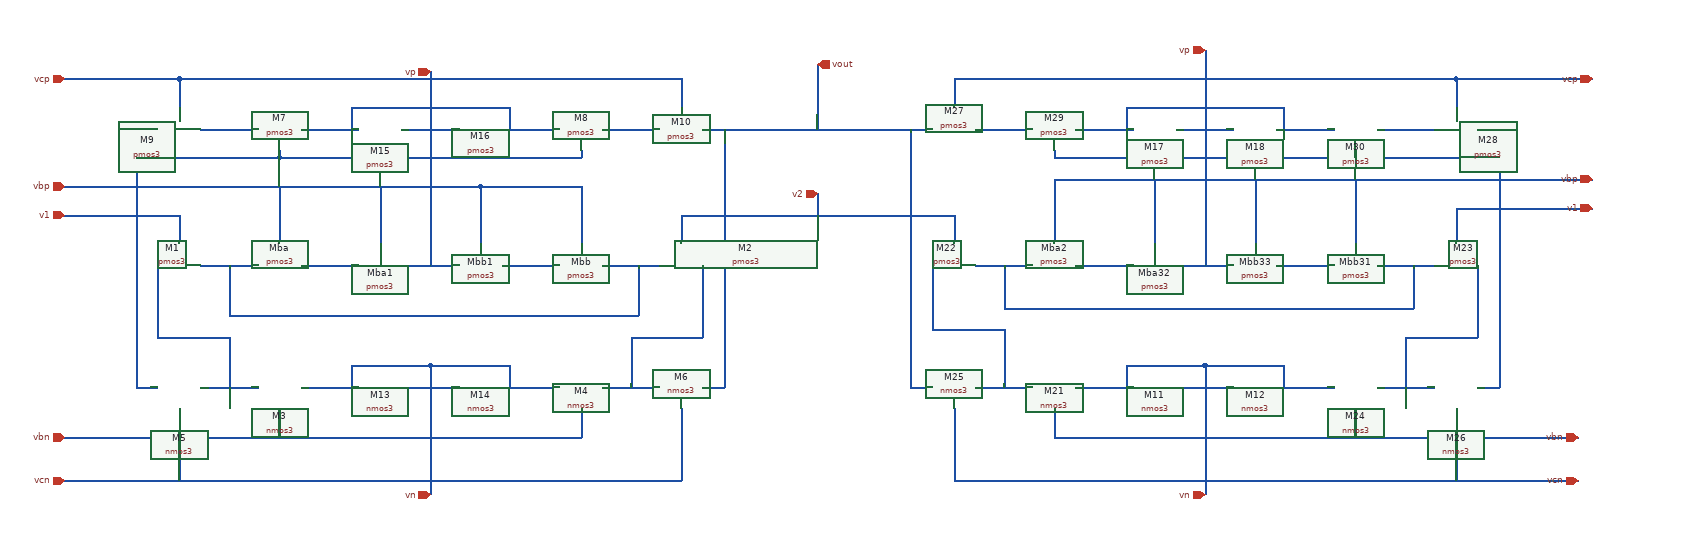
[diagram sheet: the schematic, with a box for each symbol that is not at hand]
v {xschem version=2.9.9 file_version=1.2 }
G {}
K {}
V {}
S {}
E {}
N -580 -180 -500 -180 { lab=vp}
N -540 -260 -540 -180 { lab=vp}
N -750 -150 -750 -140 { lab=#net1}
N -610 -140 -470 -140 { lab=#net1}
N -330 -150 -330 -140 { lab=#net1}
N -860 -180 -780 -180 { lab=#net2}
N -300 -180 -220 -180 { lab=#net3}
N -890 -250 -890 -210 { lab=vcp}
N -750 -250 -330 -250 { lab=vcp}
N -190 -250 -190 -210 { lab=vcp}
N -930 -250 -890 -250 { lab=vcp}
N -920 -140 -750 -140 { lab=#net1}
N -160 -180 -60 -180 { lab=vout}
N -950 -180 -920 -180 { lab=#net1}
N -950 -180 -950 180 { lab=#net1}
N -950 180 -920 180 { lab=#net1}
N -950 -140 -920 -140 { lab=#net1}
N -860 10 -780 10 { lab=#net4}
N -300 10 -220 10 { lab=#net5}
N -860 180 -780 180 { lab=#net6}
N -540 180 -540 200 { lab=vn}
N -300 180 -220 180 { lab=#net7}
N -160 180 -130 180 { lab=vout}
N -130 -180 -130 180 { lab=vout}
N -190 210 -190 310 { lab=vcn}
N -890 210 -890 310 { lab=vcn}
N -860 310 -330 310 { lab=vcn}
N -850 250 -470 250 { lab=vbn}
N -750 210 -750 250 { lab=vbn}
N -330 210 -330 250 { lab=vbn}
N -580 10 -500 10 { lab=vp}
N -540 -180 -540 10 { lab=vp}
N -190 -60 -190 -20 { lab=v2}
N -890 -60 -890 -20 { lab=v1}
N -1050 -60 -890 -60 { lab=v1}
N -750 -100 -750 -20 { lab=vbp}
N -910 -100 -470 -100 { lab=vbp}
N -330 -100 -330 -20 { lab=vbp}
N -920 10 -920 110 { lab=#net6}
N -920 110 -820 110 { lab=#net6}
N -160 10 -160 110 { lab=#net7}
N -260 110 -160 110 { lab=#net7}
N -260 110 -260 180 { lab=#net7}
N -820 110 -820 180 { lab=#net6}
N -720 10 -640 10 { lab=#net8}
N -610 -100 -610 -20 { lab=vbp}
N -1050 -100 -910 -100 { lab=vbp}
N -1000 250 -850 250 { lab=vbn}
N -1000 310 -860 310 { lab=vcn}
N -440 10 -360 10 { lab=#net9}
N -890 -250 -750 -250 { lab=vcp}
N -330 -250 -190 -250 { lab=vcp}
N -470 -140 -330 -140 { lab=#net1}
N -750 -140 -610 -140 { lab=#net1}
N -470 -100 -330 -100 { lab=vbp}
N -470 250 -330 250 { lab=vbn}
N -330 310 -190 310 { lab=vcn}
N -470 -100 -470 -20 { lab=vbp}
N -60 -180 160 -180 { lab=vout}
N 0 -270 0 -180 { lab=vout}
N 130 -180 130 180 { lab=vout}
N 130 180 160 180 { lab=vout}
N -50 -60 190 -60 { lab=v2}
N -190 -60 -50 -60 { lab=v2}
N 0 -90 0 -60 { lab=v2}
N 190 210 190 310 { lab=vcn}
N 890 210 890 310 { lab=vcn}
N 330 210 330 250 { lab=vbn}
N 750 210 750 250 { lab=vbn}
N 920 -180 950 -180 { lab=#net10}
N 950 -180 950 180 { lab=#net10}
N 920 180 950 180 { lab=#net10}
N 780 -180 860 -180 { lab=#net11}
N 780 180 860 180 { lab=#net12}
N 820 110 820 180 { lab=#net12}
N 820 110 920 110 { lab=#net12}
N 920 10 920 110 { lab=#net12}
N 780 10 860 10 { lab=#net13}
N 640 10 720 10 { lab=#net14}
N 500 10 580 10 { lab=vp}
N 360 10 440 10 { lab=#net15}
N 220 10 300 10 { lab=#net16}
N 330 -150 330 -140 { lab=#net10}
N 330 -140 950 -140 { lab=#net10}
N 750 -150 750 -140 { lab=#net10}
N 190 -250 890 -250 { lab=vcp}
N 190 -250 190 -210 { lab=vcp}
N 890 -250 890 -210 { lab=vcp}
N 330 -110 1080 -110 { lab=vbp}
N 470 -110 470 -20 { lab=vbp}
N 610 -110 610 -20 { lab=vbp}
N 330 250 1060 250 { lab=vbn}
N 190 310 1060 310 { lab=vcn}
N 540 -290 540 10 { lab=vp}
N 470 150 540 150 { lab=vn}
N 540 150 540 180 { lab=vn}
N 540 150 610 150 { lab=vn}
N 540 180 540 330 { lab=vn}
N -610 150 -540 150 { lab=vn}
N -540 150 -540 180 { lab=vn}
N -540 150 -470 150 { lab=vn}
N -540 200 -540 330 { lab=vn}
N -610 -210 -540 -210 { lab=vp}
N -540 -210 -470 -210 { lab=vp}
N 470 -210 540 -210 { lab=vp}
N 540 -210 610 -210 { lab=vp}
N 640 -180 720 -180 { lab=vp}
N 360 -180 440 -180 { lab=vp}
N 430 -210 430 -180 { lab=vp}
N 430 -210 470 -210 { lab=vp}
N 610 -210 650 -210 { lab=vp}
N 650 -210 650 -180 { lab=vp}
N -650 -210 -610 -210 { lab=vp}
N -650 -210 -650 -180 { lab=vp}
N -470 -210 -430 -210 { lab=vp}
N -430 -210 -430 -180 { lab=vp}
N -720 -180 -640 -180 { lab=vp}
N -440 -180 -360 -180 { lab=vp}
N -720 180 -640 180 { lab=vn}
N -650 150 -650 180 { lab=vn}
N -650 150 -610 150 { lab=vn}
N -470 150 -430 150 { lab=vn}
N -430 150 -430 180 { lab=vn}
N -440 180 -360 180 { lab=vn}
N -580 180 -500 180 { lab=vn}
N 360 180 440 180 { lab=vn}
N 430 150 430 180 { lab=vn}
N 430 150 470 150 { lab=vn}
N 610 150 650 150 { lab=vn}
N 650 150 650 180 { lab=vn}
N 500 180 580 180 { lab=vn}
N 640 180 720 180 { lab=vn}
N 220 -180 300 -180 { lab=#net17}
N 890 -70 890 -20 { lab=v1}
N 890 -70 1080 -70 { lab=v1}
N -1050 -250 -930 -250 { lab=vcp}
N -1050 250 -1000 250 { lab=vbn}
N -1050 310 -1000 310 { lab=vcn}
N 330 -110 330 -20 { lab=vbp}
N 750 -110 750 -20 { lab=vbp}
N 190 -60 190 -20 { lab=v2}
N 890 -250 1080 -250 { lab=vcp}
N 160 10 160 100 { lab=#net18}
N 160 100 260 100 { lab=#net18}
N 260 100 260 180 { lab=#net18}
N 220 180 300 180 { lab=#net18}
N 500 -180 540 -180 { lab=vp}
N 540 -180 580 -180 { lab=vp}
N -820 10 -820 80 {}
N -820 80 -250 80 {}
N -250 10 -250 80 {}
N 260 10 260 70 {}
N 260 70 830 70 {}
N 830 10 830 70 {}
C {madvlsi/pmos3.sym} -750 10 1 0 {name=Mba
L=0.5
W=6
body=VDD
nf=1
mult=1
ad="'int((nf+1)/2) * W/nf * 0.29'" 
pd="'2*int((nf+1)/2) * (W/nf + 0.29)'"
as="'int((nf+2)/2) * W/nf * 0.29'" 
ps="'2*int((nf+2)/2) * (W/nf + 0.29)'"
nrd="'0.29 / W'" nrs="'0.29 / W'"
sa=0 sb=0 sd=0
model=pfet_01v8
spiceprefix=X
}
C {madvlsi/nmos3.sym} -750 180 3 0 {name=M3
L=0.5
W=6
body=GND
nf=1
mult=1
ad="'int((nf+1)/2) * W/nf * 0.29'" 
pd="'2*int((nf+1)/2) * (W/nf + 0.29)'"
as="'int((nf+2)/2) * W/nf * 0.29'" 
ps="'2*int((nf+2)/2) * (W/nf + 0.29)'"
nrd="'0.29 / W'" nrs="'0.29 / W'"
sa=0 sb=0 sd=0
model=nfet_01v8
spiceprefix=X
}
C {madvlsi/pmos3.sym} -890 10 1 0 {name=M1
L=0.5
W=6
body=VDD
nf=1
mult=1
ad="'int((nf+1)/2) * W/nf * 0.29'" 
pd="'2*int((nf+1)/2) * (W/nf + 0.29)'"
as="'int((nf+2)/2) * W/nf * 0.29'" 
ps="'2*int((nf+2)/2) * (W/nf + 0.29)'"
nrd="'0.29 / W'" nrs="'0.29 / W'"
sa=0 sb=0 sd=0
model=pfet_01v8
spiceprefix=X
}
C {madvlsi/pmos3.sym} -190 10 1 0 {name=M2
L=0.5
W=6
body=VDD
nf=1
mult=1
ad="'int((nf+1)/2) * W/nf * 0.29'" 
pd="'2*int((nf+1)/2) * (W/nf + 0.29)'"
as="'int((nf+2)/2) * W/nf * 0.29'" 
ps="'2*int((nf+2)/2) * (W/nf + 0.29)'"
nrd="'0.29 / W'" nrs="'0.29 / W'"
sa=0 sb=0 sd=0
model=pfet_01v8
spiceprefix=X
}
C {devices/iopin.sym} -540 -260 3 0 {name=p1 lab=vp}
C {madvlsi/nmos3.sym} -330 180 3 0 {name=M4
L=0.5
W=6
body=GND
nf=1
mult=1
ad="'int((nf+1)/2) * W/nf * 0.29'" 
pd="'2*int((nf+1)/2) * (W/nf + 0.29)'"
as="'int((nf+2)/2) * W/nf * 0.29'" 
ps="'2*int((nf+2)/2) * (W/nf + 0.29)'"
nrd="'0.29 / W'" nrs="'0.29 / W'"
sa=0 sb=0 sd=0
model=nfet_01v8
spiceprefix=X
}
C {devices/iopin.sym} -540 330 1 0 {name=p5 lab=vn}
C {madvlsi/nmos3.sym} -890 180 3 0 {name=M5
L=0.5
W=6
body=GND
nf=1
mult=1
ad="'int((nf+1)/2) * W/nf * 0.29'" 
pd="'2*int((nf+1)/2) * (W/nf + 0.29)'"
as="'int((nf+2)/2) * W/nf * 0.29'" 
ps="'2*int((nf+2)/2) * (W/nf + 0.29)'"
nrd="'0.29 / W'" nrs="'0.29 / W'"
sa=0 sb=0 sd=0
model=nfet_01v8
spiceprefix=X
}
C {madvlsi/nmos3.sym} -190 180 3 0 {name=M6
L=0.5
W=6
body=GND
nf=1
mult=1
ad="'int((nf+1)/2) * W/nf * 0.29'" 
pd="'2*int((nf+1)/2) * (W/nf + 0.29)'"
as="'int((nf+2)/2) * W/nf * 0.29'" 
ps="'2*int((nf+2)/2) * (W/nf + 0.29)'"
nrd="'0.29 / W'" nrs="'0.29 / W'"
sa=0 sb=0 sd=0
model=nfet_01v8
spiceprefix=X
}
C {madvlsi/pmos3.sym} -890 -180 1 0 {name=M9
L=0.5
W=6
body=VDD
nf=1
mult=1
ad="'int((nf+1)/2) * W/nf * 0.29'" 
pd="'2*int((nf+1)/2) * (W/nf + 0.29)'"
as="'int((nf+2)/2) * W/nf * 0.29'" 
ps="'2*int((nf+2)/2) * (W/nf + 0.29)'"
nrd="'0.29 / W'" nrs="'0.29 / W'"
sa=0 sb=0 sd=0
model=pfet_01v8
spiceprefix=X
}
C {madvlsi/pmos3.sym} -190 -180 1 0 {name=M10
L=0.5
W=6
body=VDD
nf=1
mult=1
ad="'int((nf+1)/2) * W/nf * 0.29'" 
pd="'2*int((nf+1)/2) * (W/nf + 0.29)'"
as="'int((nf+2)/2) * W/nf * 0.29'" 
ps="'2*int((nf+2)/2) * (W/nf + 0.29)'"
nrd="'0.29 / W'" nrs="'0.29 / W'"
sa=0 sb=0 sd=0
model=pfet_01v8
spiceprefix=X
}
C {madvlsi/pmos3.sym} -750 -180 3 0 {name=M7
L=0.5
W=6
body=VDD
nf=1
mult=1
ad="'int((nf+1)/2) * W/nf * 0.29'" 
pd="'2*int((nf+1)/2) * (W/nf + 0.29)'"
as="'int((nf+2)/2) * W/nf * 0.29'" 
ps="'2*int((nf+2)/2) * (W/nf + 0.29)'"
nrd="'0.29 / W'" nrs="'0.29 / W'"
sa=0 sb=0 sd=0
model=pfet_01v8
spiceprefix=X
}
C {madvlsi/pmos3.sym} -330 -180 3 0 {name=M8
L=0.5
W=6
body=VDD
nf=1
mult=1
ad="'int((nf+1)/2) * W/nf * 0.29'" 
pd="'2*int((nf+1)/2) * (W/nf + 0.29)'"
as="'int((nf+2)/2) * W/nf * 0.29'" 
ps="'2*int((nf+2)/2) * (W/nf + 0.29)'"
nrd="'0.29 / W'" nrs="'0.29 / W'"
sa=0 sb=0 sd=0
model=pfet_01v8
spiceprefix=X
}
C {madvlsi/pmos3.sym} -330 10 1 0 {name=Mbb
L=0.5
W=6
body=VDD
nf=1
mult=1
ad="'int((nf+1)/2) * W/nf * 0.29'" 
pd="'2*int((nf+1)/2) * (W/nf + 0.29)'"
as="'int((nf+2)/2) * W/nf * 0.29'" 
ps="'2*int((nf+2)/2) * (W/nf + 0.29)'"
nrd="'0.29 / W'" nrs="'0.29 / W'"
sa=0 sb=0 sd=0
model=pfet_01v8
spiceprefix=X
}
C {madvlsi/pmos3.sym} -610 10 1 0 {name=Mba1
L=0.5
W=6
body=VDD
nf=1
mult=1
ad="'int((nf+1)/2) * W/nf * 0.29'" 
pd="'2*int((nf+1)/2) * (W/nf + 0.29)'"
as="'int((nf+2)/2) * W/nf * 0.29'" 
ps="'2*int((nf+2)/2) * (W/nf + 0.29)'"
nrd="'0.29 / W'" nrs="'0.29 / W'"
sa=0 sb=0 sd=0
model=pfet_01v8
spiceprefix=X
}
C {madvlsi/pmos3.sym} -470 10 1 0 {name=Mbb1
L=0.5
W=6
body=VDD
nf=1
mult=1
ad="'int((nf+1)/2) * W/nf * 0.29'" 
pd="'2*int((nf+1)/2) * (W/nf + 0.29)'"
as="'int((nf+2)/2) * W/nf * 0.29'" 
ps="'2*int((nf+2)/2) * (W/nf + 0.29)'"
nrd="'0.29 / W'" nrs="'0.29 / W'"
sa=0 sb=0 sd=0
model=pfet_01v8
spiceprefix=X
}
C {madvlsi/pmos3.sym} 330 10 1 0 {name=Mba2
L=0.5
W=6
body=VDD
nf=1
mult=1
ad="'int((nf+1)/2) * W/nf * 0.29'" 
pd="'2*int((nf+1)/2) * (W/nf + 0.29)'"
as="'int((nf+2)/2) * W/nf * 0.29'" 
ps="'2*int((nf+2)/2) * (W/nf + 0.29)'"
nrd="'0.29 / W'" nrs="'0.29 / W'"
sa=0 sb=0 sd=0
model=pfet_01v8
spiceprefix=X
}
C {madvlsi/nmos3.sym} 330 180 3 0 {name=M21
L=0.5
W=6
body=GND
nf=1
mult=1
ad="'int((nf+1)/2) * W/nf * 0.29'" 
pd="'2*int((nf+1)/2) * (W/nf + 0.29)'"
as="'int((nf+2)/2) * W/nf * 0.29'" 
ps="'2*int((nf+2)/2) * (W/nf + 0.29)'"
nrd="'0.29 / W'" nrs="'0.29 / W'"
sa=0 sb=0 sd=0
model=nfet_01v8
spiceprefix=X
}
C {madvlsi/pmos3.sym} 190 10 1 0 {name=M22
L=0.5
W=6
body=VDD
nf=1
mult=1
ad="'int((nf+1)/2) * W/nf * 0.29'" 
pd="'2*int((nf+1)/2) * (W/nf + 0.29)'"
as="'int((nf+2)/2) * W/nf * 0.29'" 
ps="'2*int((nf+2)/2) * (W/nf + 0.29)'"
nrd="'0.29 / W'" nrs="'0.29 / W'"
sa=0 sb=0 sd=0
model=pfet_01v8
spiceprefix=X
}
C {madvlsi/pmos3.sym} 890 10 1 0 {name=M23
L=0.5
W=6
body=VDD
nf=1
mult=1
ad="'int((nf+1)/2) * W/nf * 0.29'" 
pd="'2*int((nf+1)/2) * (W/nf + 0.29)'"
as="'int((nf+2)/2) * W/nf * 0.29'" 
ps="'2*int((nf+2)/2) * (W/nf + 0.29)'"
nrd="'0.29 / W'" nrs="'0.29 / W'"
sa=0 sb=0 sd=0
model=pfet_01v8
spiceprefix=X
}
C {madvlsi/nmos3.sym} 750 180 3 0 {name=M24
L=0.5
W=6
body=GND
nf=1
mult=1
ad="'int((nf+1)/2) * W/nf * 0.29'" 
pd="'2*int((nf+1)/2) * (W/nf + 0.29)'"
as="'int((nf+2)/2) * W/nf * 0.29'" 
ps="'2*int((nf+2)/2) * (W/nf + 0.29)'"
nrd="'0.29 / W'" nrs="'0.29 / W'"
sa=0 sb=0 sd=0
model=nfet_01v8
spiceprefix=X
}
C {madvlsi/nmos3.sym} 190 180 3 0 {name=M25
L=0.5
W=6
body=GND
nf=1
mult=1
ad="'int((nf+1)/2) * W/nf * 0.29'" 
pd="'2*int((nf+1)/2) * (W/nf + 0.29)'"
as="'int((nf+2)/2) * W/nf * 0.29'" 
ps="'2*int((nf+2)/2) * (W/nf + 0.29)'"
nrd="'0.29 / W'" nrs="'0.29 / W'"
sa=0 sb=0 sd=0
model=nfet_01v8
spiceprefix=X
}
C {madvlsi/nmos3.sym} 890 180 3 0 {name=M26
L=0.5
W=6
body=GND
nf=1
mult=1
ad="'int((nf+1)/2) * W/nf * 0.29'" 
pd="'2*int((nf+1)/2) * (W/nf + 0.29)'"
as="'int((nf+2)/2) * W/nf * 0.29'" 
ps="'2*int((nf+2)/2) * (W/nf + 0.29)'"
nrd="'0.29 / W'" nrs="'0.29 / W'"
sa=0 sb=0 sd=0
model=nfet_01v8
spiceprefix=X
}
C {madvlsi/pmos3.sym} 190 -180 1 0 {name=M27
L=0.5
W=6
body=VDD
nf=1
mult=1
ad="'int((nf+1)/2) * W/nf * 0.29'" 
pd="'2*int((nf+1)/2) * (W/nf + 0.29)'"
as="'int((nf+2)/2) * W/nf * 0.29'" 
ps="'2*int((nf+2)/2) * (W/nf + 0.29)'"
nrd="'0.29 / W'" nrs="'0.29 / W'"
sa=0 sb=0 sd=0
model=pfet_01v8
spiceprefix=X
}
C {madvlsi/pmos3.sym} 890 -180 1 0 {name=M28
L=0.5
W=6
body=VDD
nf=1
mult=1
ad="'int((nf+1)/2) * W/nf * 0.29'" 
pd="'2*int((nf+1)/2) * (W/nf + 0.29)'"
as="'int((nf+2)/2) * W/nf * 0.29'" 
ps="'2*int((nf+2)/2) * (W/nf + 0.29)'"
nrd="'0.29 / W'" nrs="'0.29 / W'"
sa=0 sb=0 sd=0
model=pfet_01v8
spiceprefix=X
}
C {madvlsi/pmos3.sym} 330 -180 3 0 {name=M29
L=0.5
W=6
body=VDD
nf=1
mult=1
ad="'int((nf+1)/2) * W/nf * 0.29'" 
pd="'2*int((nf+1)/2) * (W/nf + 0.29)'"
as="'int((nf+2)/2) * W/nf * 0.29'" 
ps="'2*int((nf+2)/2) * (W/nf + 0.29)'"
nrd="'0.29 / W'" nrs="'0.29 / W'"
sa=0 sb=0 sd=0
model=pfet_01v8
spiceprefix=X
}
C {madvlsi/pmos3.sym} 750 -180 3 0 {name=M30
L=0.5
W=6
body=VDD
nf=1
mult=1
ad="'int((nf+1)/2) * W/nf * 0.29'" 
pd="'2*int((nf+1)/2) * (W/nf + 0.29)'"
as="'int((nf+2)/2) * W/nf * 0.29'" 
ps="'2*int((nf+2)/2) * (W/nf + 0.29)'"
nrd="'0.29 / W'" nrs="'0.29 / W'"
sa=0 sb=0 sd=0
model=pfet_01v8
spiceprefix=X
}
C {madvlsi/pmos3.sym} 750 10 1 0 {name=Mbb31
L=0.5
W=6
body=VDD
nf=1
mult=1
ad="'int((nf+1)/2) * W/nf * 0.29'" 
pd="'2*int((nf+1)/2) * (W/nf + 0.29)'"
as="'int((nf+2)/2) * W/nf * 0.29'" 
ps="'2*int((nf+2)/2) * (W/nf + 0.29)'"
nrd="'0.29 / W'" nrs="'0.29 / W'"
sa=0 sb=0 sd=0
model=pfet_01v8
spiceprefix=X
}
C {madvlsi/pmos3.sym} 470 10 1 0 {name=Mba32
L=0.5
W=6
body=VDD
nf=1
mult=1
ad="'int((nf+1)/2) * W/nf * 0.29'" 
pd="'2*int((nf+1)/2) * (W/nf + 0.29)'"
as="'int((nf+2)/2) * W/nf * 0.29'" 
ps="'2*int((nf+2)/2) * (W/nf + 0.29)'"
nrd="'0.29 / W'" nrs="'0.29 / W'"
sa=0 sb=0 sd=0
model=pfet_01v8
spiceprefix=X
}
C {madvlsi/pmos3.sym} 610 10 1 0 {name=Mbb33
L=0.5
W=6
body=VDD
nf=1
mult=1
ad="'int((nf+1)/2) * W/nf * 0.29'" 
pd="'2*int((nf+1)/2) * (W/nf + 0.29)'"
as="'int((nf+2)/2) * W/nf * 0.29'" 
ps="'2*int((nf+2)/2) * (W/nf + 0.29)'"
nrd="'0.29 / W'" nrs="'0.29 / W'"
sa=0 sb=0 sd=0
model=pfet_01v8
spiceprefix=X
}
C {devices/iopin.sym} 540 -290 3 0 {name=p13 lab=vp}
C {madvlsi/nmos3.sym} 470 180 1 0 {name=M11
L=0.5
W=6
body=GND
nf=1
mult=1
ad="'int((nf+1)/2) * W/nf * 0.29'" 
pd="'2*int((nf+1)/2) * (W/nf + 0.29)'"
as="'int((nf+2)/2) * W/nf * 0.29'" 
ps="'2*int((nf+2)/2) * (W/nf + 0.29)'"
nrd="'0.29 / W'" nrs="'0.29 / W'"
sa=0 sb=0 sd=0
model=nfet_01v8
spiceprefix=X
}
C {madvlsi/nmos3.sym} 610 180 1 0 {name=M12
L=0.5
W=6
body=GND
nf=1
mult=1
ad="'int((nf+1)/2) * W/nf * 0.29'" 
pd="'2*int((nf+1)/2) * (W/nf + 0.29)'"
as="'int((nf+2)/2) * W/nf * 0.29'" 
ps="'2*int((nf+2)/2) * (W/nf + 0.29)'"
nrd="'0.29 / W'" nrs="'0.29 / W'"
sa=0 sb=0 sd=0
model=nfet_01v8
spiceprefix=X
}
C {devices/iopin.sym} 540 330 1 0 {name=p14 lab=vn}
C {madvlsi/nmos3.sym} -610 180 1 0 {name=M13
L=0.5
W=6
body=GND
nf=1
mult=1
ad="'int((nf+1)/2) * W/nf * 0.29'" 
pd="'2*int((nf+1)/2) * (W/nf + 0.29)'"
as="'int((nf+2)/2) * W/nf * 0.29'" 
ps="'2*int((nf+2)/2) * (W/nf + 0.29)'"
nrd="'0.29 / W'" nrs="'0.29 / W'"
sa=0 sb=0 sd=0
model=nfet_01v8
spiceprefix=X
}
C {madvlsi/nmos3.sym} -470 180 1 0 {name=M14
L=0.5
W=6
body=GND
nf=1
mult=1
ad="'int((nf+1)/2) * W/nf * 0.29'" 
pd="'2*int((nf+1)/2) * (W/nf + 0.29)'"
as="'int((nf+2)/2) * W/nf * 0.29'" 
ps="'2*int((nf+2)/2) * (W/nf + 0.29)'"
nrd="'0.29 / W'" nrs="'0.29 / W'"
sa=0 sb=0 sd=0
model=nfet_01v8
spiceprefix=X
}
C {madvlsi/pmos3.sym} -610 -180 1 0 {name=M15
L=0.5
W=6
body=VDD
nf=1
mult=1
ad="'int((nf+1)/2) * W/nf * 0.29'" 
pd="'2*int((nf+1)/2) * (W/nf + 0.29)'"
as="'int((nf+2)/2) * W/nf * 0.29'" 
ps="'2*int((nf+2)/2) * (W/nf + 0.29)'"
nrd="'0.29 / W'" nrs="'0.29 / W'"
sa=0 sb=0 sd=0
model=pfet_01v8
spiceprefix=X
}
C {madvlsi/pmos3.sym} -470 -180 1 0 {name=M16
L=0.5
W=6
body=VDD
nf=1
mult=1
ad="'int((nf+1)/2) * W/nf * 0.29'" 
pd="'2*int((nf+1)/2) * (W/nf + 0.29)'"
as="'int((nf+2)/2) * W/nf * 0.29'" 
ps="'2*int((nf+2)/2) * (W/nf + 0.29)'"
nrd="'0.29 / W'" nrs="'0.29 / W'"
sa=0 sb=0 sd=0
model=pfet_01v8
spiceprefix=X
}
C {madvlsi/pmos3.sym} 470 -180 1 0 {name=M17
L=0.5
W=6
body=VDD
nf=1
mult=1
ad="'int((nf+1)/2) * W/nf * 0.29'" 
pd="'2*int((nf+1)/2) * (W/nf + 0.29)'"
as="'int((nf+2)/2) * W/nf * 0.29'" 
ps="'2*int((nf+2)/2) * (W/nf + 0.29)'"
nrd="'0.29 / W'" nrs="'0.29 / W'"
sa=0 sb=0 sd=0
model=pfet_01v8
spiceprefix=X
}
C {madvlsi/pmos3.sym} 610 -180 1 0 {name=M18
L=0.5
W=6
body=VDD
nf=1
mult=1
ad="'int((nf+1)/2) * W/nf * 0.29'" 
pd="'2*int((nf+1)/2) * (W/nf + 0.29)'"
as="'int((nf+2)/2) * W/nf * 0.29'" 
ps="'2*int((nf+2)/2) * (W/nf + 0.29)'"
nrd="'0.29 / W'" nrs="'0.29 / W'"
sa=0 sb=0 sd=0
model=pfet_01v8
spiceprefix=X
}
C {devices/opin.sym} 0 -270 3 0 {name=p16 lab=vout}
C {devices/ipin.sym} 0 -90 1 0 {name=p4 lab=v2}
C {devices/ipin.sym} -1050 -60 0 0 {name=p9 lab=v1}
C {devices/ipin.sym} 1080 -70 2 0 {name=p3 lab=v1}
C {devices/ipin.sym} 1080 -110 2 0 {name=p15 lab=vbp}
C {devices/ipin.sym} -1050 -100 0 0 {name=p7 lab=vbp}
C {devices/ipin.sym} -1050 -250 0 0 {name=p2 lab=vcp}
C {devices/ipin.sym} -1050 250 0 0 {name=p10 lab=vbn}
C {devices/ipin.sym} -1050 310 0 0 {name=p17 lab=vcn}
C {devices/ipin.sym} 1060 250 2 0 {name=p6 lab=vbn}
C {devices/ipin.sym} 1060 310 2 0 {name=p8 lab=vcn}
C {devices/ipin.sym} 1080 -250 2 0 {name=p11 lab=vcp}
